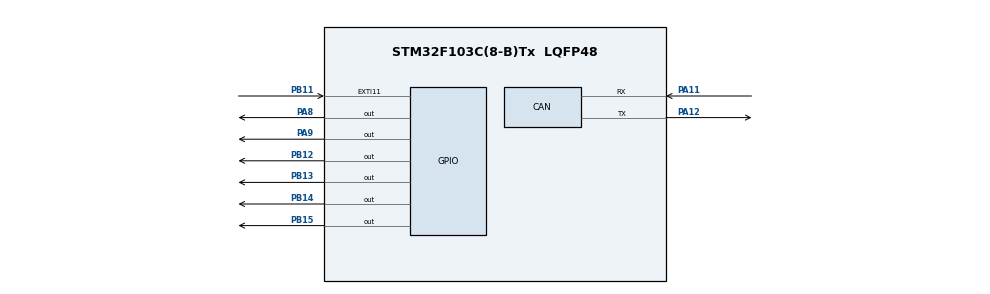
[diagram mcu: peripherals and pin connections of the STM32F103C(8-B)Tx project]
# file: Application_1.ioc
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CAN.BS1=CAN_BS1_2TQ
CAN.CalculateTimeBit=8000
CAN.CalculateTimeQuantum=2000.0
Mcu.Family=STM32F1
Mcu.Name=STM32F103C(8-B)Tx
Mcu.Package=LQFP48
NVIC.CAN1_RX1_IRQn=true\:0\:0\:false\:false\:true\:true\:true
NVIC.EXTI15_10_IRQn=true\:0\:0\:false\:false\:true\:true\:true
NVIC.PriorityGroup=NVIC_PRIORITYGROUP_4
NVIC.USB_LP_CAN1_RX0_IRQn=true\:0\:0\:false\:false\:true\:true\:true
PA11.Mode=Master
PA11.Signal=CAN_RX
PA12.Mode=Master
PA12.Signal=CAN_TX
PA13.Mode=Serial_Wire
PA13.Signal=SYS_JTMS-SWDIO
PA14.Mode=Serial_Wire
PA14.Signal=SYS_JTCK-SWCLK
PA8.Signal=GPIO_Output
PA9.Signal=GPIO_Output
PB11.GPIO_ModeDefaultEXTI=GPIO_MODE_IT_FALLING
PB11.Signal=GPXTI11
PB12.Signal=GPIO_Output
PB13.Signal=GPIO_Output
PB14.Signal=GPIO_Output
PB15.Signal=GPIO_Output
ProjectManager.HeapSize=0x200
ProjectManager.StackSize=0x400
ProjectManager.TargetToolchain=STM32CubeIDE
RCC.APB1Freq_Value=8000000
RCC.APB2Freq_Value=8000000
board=custom

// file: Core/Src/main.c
/* USER CODE BEGIN Header */
/**
 ******************************************************************************
 * @file           : main.c
 * @brief          : Main program body
 ******************************************************************************
 * @attention
 *
 * <h2><center>&copy; Copyright (c) 2023 STMicroelectronics.
 * All rights reserved.</center></h2>
 *
 * This software component is licensed by ST under BSD 3-Clause license,
 * the "License"; You may not use this file except in compliance with the
 * License. You may obtain a copy of the License at:
 *                        opensource.org/licenses/BSD-3-Clause
 *
 ******************************************************************************
 */
/* USER CODE END Header */
#include "main.h"

/* USER CODE BEGIN Includes */
#include "../Inc/standardTypes.h"

#include "../Inc/SCB_Interface.h"
#include "../Inc/CLCD_Interface.h"
/* USER CODE END Includes */

/* USER CODE BEGIN PTD */
/* declaring a pointer to function */
typedef void(* fun_ptr)(void);
/* USER CODE END PTD */

/* USER CODE BEGIN PV */

/***************************************************************************
 *                           Global variables                              *
 ***************************************************************************/

/* CAN variables: */
/* CAN header type */
CAN_HandleTypeDef hcan;
/* buffer to receive the data */
uint8_t CAN_RxBuffer;
/* iterator to access each element in the CAN_RxBuffer */
uint8_t CAN_i = 0;
/* TX and RX headers */
CAN_RxHeaderTypeDef RxHeader;
/*-----------------------------------------------------*/

/* Flags: */
/* data received flag */
uint8_t Flag_CAN = 0;
/* switch the application flag */
uint8_t FLAG_buttonPressed = 0;
/*--------------------------------*/

fun_ptr addr_to_call = 0;

/* USER CODE END PV */

void SystemClock_Config(void);
static void MX_GPIO_Init(void);
static void MX_CAN_Init(void);
void JumpToBootLoader(void);

int main(void)
{
/* Local variables: */
	uint8_t Flag_once = 1;

	/* CAN RX header parameters */
	RxHeader.DLC = 1;
	RxHeader.IDE = CAN_ID_STD;
	RxHeader.RTR = CAN_RTR_DATA;
	RxHeader.StdId = 0x100;

	/* Reset of all peripherals, Initializes the Flash interface and the Systick. */
	HAL_Init();

	/* Initialize all configured peripherals */
	MX_GPIO_Init();
/* CAN: */
	/* initializing the CAN driver. */
	MX_CAN_Init();
	/* Start the CAN driver */
	HAL_CAN_Start(&hcan);
	/* Enable the CAN interrupt mode */
	HAL_CAN_ActivateNotification(&hcan, CAN_IT_RX_FIFO0_MSG_PENDING);

/* LCD: */
	/* initialize the LCD */
	CLCD_Init();
	/* clear the LCD */
	CLCD_ClearDisplay();
	/* write the string on the LCD */
	CLCD_WriteString("App_1");

/* Super loop */
	while (1)
	{
		/* if the button is pressed */
		if(FLAG_buttonPressed)
		{
			/* delay for debouncing */
			HAL_Delay(100);
			/* jump to the bootloader */
			JumpToBootLoader();
		}
		else
		{
			/* if the CAN flag is raised */
			if(Flag_CAN)
			{
				if(Flag_once)
				{
					Flag_once = 0;
					/* clear the LCD */
					CLCD_ClearDisplay();
					/* write the string on the LCD */
					CLCD_WriteString("available update");
					/* moving cursor to the second raw */
					CLCD_MoveCursor(1, 0);
					/* write the string on the LCD */
					CLCD_WriteString("press the button");
				}
				if(FLAG_buttonPressed)
				{
					HAL_Delay(100);
					JumpToBootLoader();
				}
			}
			/* if the CAN flag is not raised yet */
			else
			{
				/* do nothing */
			}
		}
	}
}

void SystemClock_Config(void)
{
	RCC_OscInitTypeDef RCC_OscInitStruct = {0};
	RCC_ClkInitTypeDef RCC_ClkInitStruct = {0};

	/** Initializes the RCC Oscillators according to the specified parameters
	 * in the RCC_OscInitTypeDef structure.
	 */
	RCC_OscInitStruct.OscillatorType = RCC_OSCILLATORTYPE_HSI;
	RCC_OscInitStruct.HSIState = RCC_HSI_ON;
	RCC_OscInitStruct.HSICalibrationValue = RCC_HSICALIBRATION_DEFAULT;
	RCC_OscInitStruct.PLL.PLLState = RCC_PLL_NONE;
	if (HAL_RCC_OscConfig(&RCC_OscInitStruct) != HAL_OK)
	{
		Error_Handler();
	}
	/** Initializes the CPU, AHB and APB buses clocks
	 */
	RCC_ClkInitStruct.ClockType = RCC_CLOCKTYPE_HCLK|RCC_CLOCKTYPE_SYSCLK
			|RCC_CLOCKTYPE_PCLK1|RCC_CLOCKTYPE_PCLK2;
	RCC_ClkInitStruct.SYSCLKSource = RCC_SYSCLKSOURCE_HSI;
	RCC_ClkInitStruct.AHBCLKDivider = RCC_SYSCLK_DIV1;
	RCC_ClkInitStruct.APB1CLKDivider = RCC_HCLK_DIV1;
	RCC_ClkInitStruct.APB2CLKDivider = RCC_HCLK_DIV1;

	if (HAL_RCC_ClockConfig(&RCC_ClkInitStruct, FLASH_LATENCY_0) != HAL_OK)
	{
		Error_Handler();
	}
}

static void MX_CAN_Init(void)
{

	hcan.Instance = CAN1;
	hcan.Init.Prescaler = 16;
	hcan.Init.Mode = CAN_MODE_NORMAL;
	hcan.Init.SyncJumpWidth = CAN_SJW_1TQ;
	hcan.Init.TimeSeg1 = CAN_BS1_2TQ;
	hcan.Init.TimeSeg2 = CAN_BS2_1TQ;
	hcan.Init.TimeTriggeredMode = DISABLE;
	hcan.Init.AutoBusOff = DISABLE;
	hcan.Init.AutoWakeUp = DISABLE;
	hcan.Init.AutoRetransmission = DISABLE;
	hcan.Init.ReceiveFifoLocked = DISABLE;
	hcan.Init.TransmitFifoPriority = DISABLE;
	if (HAL_CAN_Init(&hcan) != HAL_OK)
	{
		Error_Handler();
	}
	/* USER CODE BEGIN CAN_Init 2 */
	CAN_FilterTypeDef canfilterconfig;

	canfilterconfig.FilterActivation = CAN_FILTER_ENABLE;
	canfilterconfig.FilterBank = 10;  // anything between 0 to SlaveStartFilterBank
	canfilterconfig.FilterFIFOAssignment = CAN_RX_FIFO0;
	canfilterconfig.FilterIdHigh = 0x0000;
	canfilterconfig.FilterIdLow = 0x0000;
	canfilterconfig.FilterMaskIdHigh = 0x0000;
	canfilterconfig.FilterMaskIdLow = 0x0000;
	canfilterconfig.FilterMode = CAN_FILTERMODE_IDMASK;
	canfilterconfig.FilterScale = CAN_FILTERSCALE_32BIT;
	canfilterconfig.SlaveStartFilterBank = 0;  // 13 to 27 are assigned to slave CAN (CAN 2) OR 0 to 12 are assigned to CAN1

	HAL_CAN_ConfigFilter(&hcan, &canfilterconfig);

	/* USER CODE END CAN_Init 2 */

}

static void MX_GPIO_Init(void)
{
  GPIO_InitTypeDef GPIO_InitStruct = {0};

  /* GPIO Ports Clock Enable */
  __HAL_RCC_GPIOA_CLK_ENABLE();
  __HAL_RCC_GPIOB_CLK_ENABLE();

  /*Configure GPIO pin Output Level */
  HAL_GPIO_WritePin(GPIOA, GPIO_PIN_1|GPIO_PIN_2|GPIO_PIN_8|GPIO_PIN_9, GPIO_PIN_RESET);

  /*Configure GPIO pin Output Level */
  HAL_GPIO_WritePin(GPIOB, GPIO_PIN_12|GPIO_PIN_13|GPIO_PIN_14|GPIO_PIN_15, GPIO_PIN_RESET);

  /*Configure GPIO pins : PA1 PA2 PA8 PA9 */
  GPIO_InitStruct.Pin = GPIO_PIN_1|GPIO_PIN_2|GPIO_PIN_8|GPIO_PIN_9;
  GPIO_InitStruct.Mode = GPIO_MODE_OUTPUT_PP;
  GPIO_InitStruct.Pull = GPIO_NOPULL;
  GPIO_InitStruct.Speed = GPIO_SPEED_FREQ_LOW;
  HAL_GPIO_Init(GPIOA, &GPIO_InitStruct);

  /*Configure GPIO pin : PB11 */
  GPIO_InitStruct.Pin = GPIO_PIN_11;
  GPIO_InitStruct.Mode = GPIO_MODE_IT_FALLING;
  GPIO_InitStruct.Pull = GPIO_NOPULL;
  HAL_GPIO_Init(GPIOB, &GPIO_InitStruct);

  /*Configure GPIO pins : PB12 PB13 PB14 PB15 */
  GPIO_InitStruct.Pin = GPIO_PIN_12|GPIO_PIN_13|GPIO_PIN_14|GPIO_PIN_15;
  GPIO_InitStruct.Mode = GPIO_MODE_OUTPUT_PP;
  GPIO_InitStruct.Pull = GPIO_NOPULL;
  GPIO_InitStruct.Speed = GPIO_SPEED_FREQ_LOW;
  HAL_GPIO_Init(GPIOB, &GPIO_InitStruct);

  /* EXTI interrupt init*/
  HAL_NVIC_SetPriority(EXTI15_10_IRQn, 0, 0);
  HAL_NVIC_EnableIRQ(EXTI15_10_IRQn);

}

/* USER CODE BEGIN 4 */

void JumpToBootLoader(void)
{
	/* deinitializing the HAL */
	HAL_DeInit();

	/* shift the vector table to that of Bootloader */
	SCB_ShiftInterruptVectorTable(0x08000000);

	/* Apply soft reset */
	SCB_PerformSoftReset();
}

/***************************************************************
 * Service name: HAL_CAN_RxFifo0MsgPendingCallback
 *
 * parameter in: None
 *
 * parameter in/out: None
 *
 * parameter out: None
 *
 * return: void
 *
 * description: CAN callback function
 ***************************************************************/
void HAL_CAN_RxFifo0MsgPendingCallback(CAN_HandleTypeDef *hcan)
{
	/* raise the CAN flag */
	Flag_CAN = 1;
	/* toggle a led that indicates a reception*/
	HAL_GPIO_TogglePin(GPIOA, GPIO_PIN_1);
	/* receive in the CAN RX buffer */
	HAL_CAN_GetRxMessage(hcan, CAN_RX_FIFO0, &RxHeader, &CAN_RxBuffer);

}

/***************************************************************
 * Service name: HAL_GPIO_EXTI_Callback
 *
 * parameter in: None
 *
 * parameter in/out: None
 *
 * parameter out: None
 *
 * return: void
 *
 * description: External callback function
 ***************************************************************/
void HAL_GPIO_EXTI_Callback(uint16_t GPIO_Pins)
{
	/* raise the switch flag */
	FLAG_buttonPressed = 1;
}

/* USER CODE END 4 */

void Error_Handler(void)
{
	__disable_irq();
	while (1)
	{
	}
}

/************************ (C) COPYRIGHT STMicroelectronics *****END OF FILE****/
